One B-rep face of a CAD part: STEP entity #1066.
In plain terms, the planar face has unit normal (1, 0, 0).
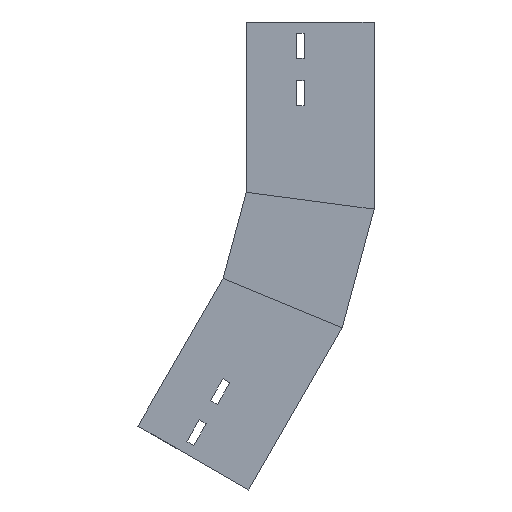
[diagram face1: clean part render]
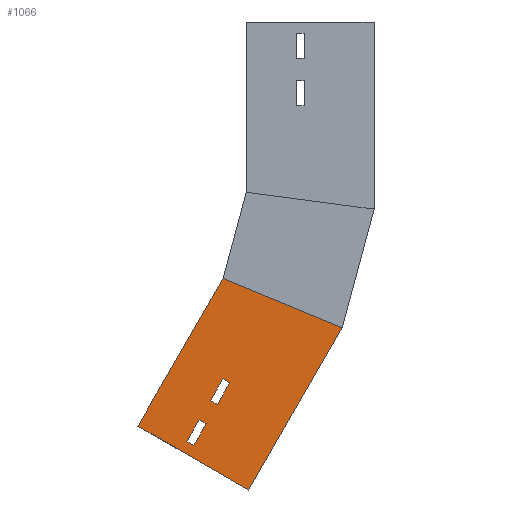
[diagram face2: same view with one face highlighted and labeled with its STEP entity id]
Its self-contained STEP definition (entity closure, numbers rounded to 3 decimals):
#13 = VERTEX_POINT ( 'NONE', #651 ) ;
#14 = AXIS2_PLACEMENT_3D ( 'NONE', #639, #719, #742 ) ;
#18 = EDGE_CURVE ( 'NONE', #248, #52, #770, .T. ) ;
#52 = VERTEX_POINT ( 'NONE', #635 ) ;
#59 = EDGE_LOOP ( 'NONE', ( #1169, #917, #893, #732 ) ) ;
#70 = CARTESIAN_POINT ( 'NONE',  ( 0., 68.5, -31.835 ) ) ;
#85 = DIRECTION ( 'NONE',  ( 0., 1., 0. ) ) ;
#97 = CARTESIAN_POINT ( 'NONE',  ( 0., 61.5, -9.835 ) ) ;
#106 = ORIENTED_EDGE ( 'NONE', *, *, #1218, .T. ) ;
#117 = VERTEX_POINT ( 'NONE', #451 ) ;
#122 = LINE ( 'NONE', #802, #597 ) ;
#126 = CARTESIAN_POINT ( 'NONE',  ( 0., 68.5, -31.835 ) ) ;
#133 = ORIENTED_EDGE ( 'NONE', *, *, #1371, .T. ) ;
#168 = VECTOR ( 'NONE', #256, 1000. ) ;
#196 = DIRECTION ( 'NONE',  ( 0., 0., -1. ) ) ;
#244 = ORIENTED_EDGE ( 'NONE', *, *, #18, .T. ) ;
#248 = VERTEX_POINT ( 'NONE', #860 ) ;
#256 = DIRECTION ( 'NONE',  ( 0., 0., 1. ) ) ;
#264 = CARTESIAN_POINT ( 'NONE',  ( 0., 112.5, 0. ) ) ;
#284 = FACE_OUTER_BOUND ( 'NONE', #1069, .T. ) ;
#304 = CARTESIAN_POINT ( 'NONE',  ( 0., 0., 0. ) ) ;
#309 = EDGE_CURVE ( 'NONE', #1263, #52, #797, .T. ) ;
#346 = VERTEX_POINT ( 'NONE', #126 ) ;
#347 = EDGE_CURVE ( 'NONE', #13, #346, #1406, .T. ) ;
#373 = LINE ( 'NONE', #382, #895 ) ;
#376 = EDGE_CURVE ( 'NONE', #1416, #1137, #835, .T. ) ;
#382 = CARTESIAN_POINT ( 'NONE',  ( 0., 68.5, -51.505 ) ) ;
#412 = ORIENTED_EDGE ( 'NONE', *, *, #309, .F. ) ;
#429 = CARTESIAN_POINT ( 'NONE',  ( 0., 0., 0. ) ) ;
#451 = CARTESIAN_POINT ( 'NONE',  ( 0., 61.5, -31.835 ) ) ;
#459 = VERTEX_POINT ( 'NONE', #97 ) ;
#461 = EDGE_CURVE ( 'NONE', #248, #1228, #535, .T. ) ;
#500 = VECTOR ( 'NONE', #512, 1000. ) ;
#512 = DIRECTION ( 'NONE',  ( 0., 0., -1. ) ) ;
#522 = VECTOR ( 'NONE', #1248, 1000. ) ;
#535 = LINE ( 'NONE', #429, #776 ) ;
#589 = CARTESIAN_POINT ( 'NONE',  ( 0., 68.5, -51.505 ) ) ;
#597 = VECTOR ( 'NONE', #679, 1000. ) ;
#609 = EDGE_CURVE ( 'NONE', #1132, #1189, #373, .T. ) ;
#610 = PLANE ( 'NONE',  #14 ) ;
#633 = EDGE_CURVE ( 'NONE', #346, #117, #1315, .T. ) ;
#635 = CARTESIAN_POINT ( 'NONE',  ( 0., 0., -164.6 ) ) ;
#639 = CARTESIAN_POINT ( 'NONE',  ( 0., 0., 0. ) ) ;
#645 = DIRECTION ( 'NONE',  ( 0., 0., 1. ) ) ;
#651 = CARTESIAN_POINT ( 'NONE',  ( 0., 68.5, -9.835 ) ) ;
#679 = DIRECTION ( 'NONE',  ( 0., -1., 0. ) ) ;
#715 = EDGE_CURVE ( 'NONE', #459, #13, #1124, .T. ) ;
#719 = DIRECTION ( 'NONE',  ( -1., 0., 0. ) ) ;
#720 = EDGE_CURVE ( 'NONE', #117, #459, #753, .T. ) ;
#732 = ORIENTED_EDGE ( 'NONE', *, *, #720, .T. ) ;
#735 = FACE_BOUND ( 'NONE', #59, .T. ) ;
#742 = DIRECTION ( 'NONE',  ( 0., 0., 1. ) ) ;
#753 = LINE ( 'NONE', #779, #846 ) ;
#770 = LINE ( 'NONE', #304, #1203 ) ;
#776 = VECTOR ( 'NONE', #781, 1000. ) ;
#779 = CARTESIAN_POINT ( 'NONE',  ( 0., 61.5, -9.835 ) ) ;
#781 = DIRECTION ( 'NONE',  ( 0., 1., 0. ) ) ;
#787 = CARTESIAN_POINT ( 'NONE',  ( 0., 68.5, -9.835 ) ) ;
#797 = LINE ( 'NONE', #947, #815 ) ;
#799 = VECTOR ( 'NONE', #85, 1000. ) ;
#802 = CARTESIAN_POINT ( 'NONE',  ( 0., 68.5, -73.505 ) ) ;
#815 = VECTOR ( 'NONE', #1142, 1000. ) ;
#835 = LINE ( 'NONE', #953, #168 ) ;
#846 = VECTOR ( 'NONE', #645, 1000. ) ;
#860 = CARTESIAN_POINT ( 'NONE',  ( 0., 0., 0. ) ) ;
#865 = ORIENTED_EDGE ( 'NONE', *, *, #1407, .F. ) ;
#868 = CARTESIAN_POINT ( 'NONE',  ( 0., 68.5, -51.505 ) ) ;
#893 = ORIENTED_EDGE ( 'NONE', *, *, #633, .T. ) ;
#895 = VECTOR ( 'NONE', #1070, 1000. ) ;
#917 = ORIENTED_EDGE ( 'NONE', *, *, #347, .T. ) ;
#934 = ORIENTED_EDGE ( 'NONE', *, *, #461, .F. ) ;
#947 = CARTESIAN_POINT ( 'NONE',  ( 0., 21.301, -161.796 ) ) ;
#953 = CARTESIAN_POINT ( 'NONE',  ( 0., 61.5, -51.505 ) ) ;
#966 = CARTESIAN_POINT ( 'NONE',  ( 0., 112.5, 0. ) ) ;
#978 = ORIENTED_EDGE ( 'NONE', *, *, #609, .T. ) ;
#999 = DIRECTION ( 'NONE',  ( 0., -1., 0. ) ) ;
#1052 = ORIENTED_EDGE ( 'NONE', *, *, #376, .T. ) ;
#1066 = ADVANCED_FACE ( 'NONE', ( #1440, #284, #735 ), #610, .F. ) ;
#1069 = EDGE_LOOP ( 'NONE', ( #865, #934, #244, #412 ) ) ;
#1070 = DIRECTION ( 'NONE',  ( 0., 0., -1. ) ) ;
#1073 = LINE ( 'NONE', #589, #1296 ) ;
#1086 = CARTESIAN_POINT ( 'NONE',  ( 0., 61.5, -73.505 ) ) ;
#1119 = CARTESIAN_POINT ( 'NONE',  ( 0., 68.5, -9.835 ) ) ;
#1124 = LINE ( 'NONE', #1119, #799 ) ;
#1127 = CARTESIAN_POINT ( 'NONE',  ( 0., 68.5, -73.505 ) ) ;
#1132 = VERTEX_POINT ( 'NONE', #868 ) ;
#1137 = VERTEX_POINT ( 'NONE', #1335 ) ;
#1142 = DIRECTION ( 'NONE',  ( 0., -0.991, -0.131 ) ) ;
#1149 = CARTESIAN_POINT ( 'NONE',  ( 0., 112.5, -149.789 ) ) ;
#1164 = DIRECTION ( 'NONE',  ( 0., 1., 0. ) ) ;
#1169 = ORIENTED_EDGE ( 'NONE', *, *, #715, .T. ) ;
#1189 = VERTEX_POINT ( 'NONE', #1127 ) ;
#1203 = VECTOR ( 'NONE', #196, 1000. ) ;
#1218 = EDGE_CURVE ( 'NONE', #1189, #1416, #122, .T. ) ;
#1228 = VERTEX_POINT ( 'NONE', #264 ) ;
#1248 = DIRECTION ( 'NONE',  ( 0., 0., -1. ) ) ;
#1263 = VERTEX_POINT ( 'NONE', #1149 ) ;
#1287 = EDGE_LOOP ( 'NONE', ( #133, #978, #106, #1052 ) ) ;
#1296 = VECTOR ( 'NONE', #1164, 1000. ) ;
#1315 = LINE ( 'NONE', #70, #1429 ) ;
#1335 = CARTESIAN_POINT ( 'NONE',  ( 0., 61.5, -51.505 ) ) ;
#1371 = EDGE_CURVE ( 'NONE', #1137, #1132, #1073, .T. ) ;
#1406 = LINE ( 'NONE', #787, #522 ) ;
#1407 = EDGE_CURVE ( 'NONE', #1228, #1263, #1418, .T. ) ;
#1416 = VERTEX_POINT ( 'NONE', #1086 ) ;
#1418 = LINE ( 'NONE', #966, #500 ) ;
#1429 = VECTOR ( 'NONE', #999, 1000. ) ;
#1440 = FACE_BOUND ( 'NONE', #1287, .T. ) ;
